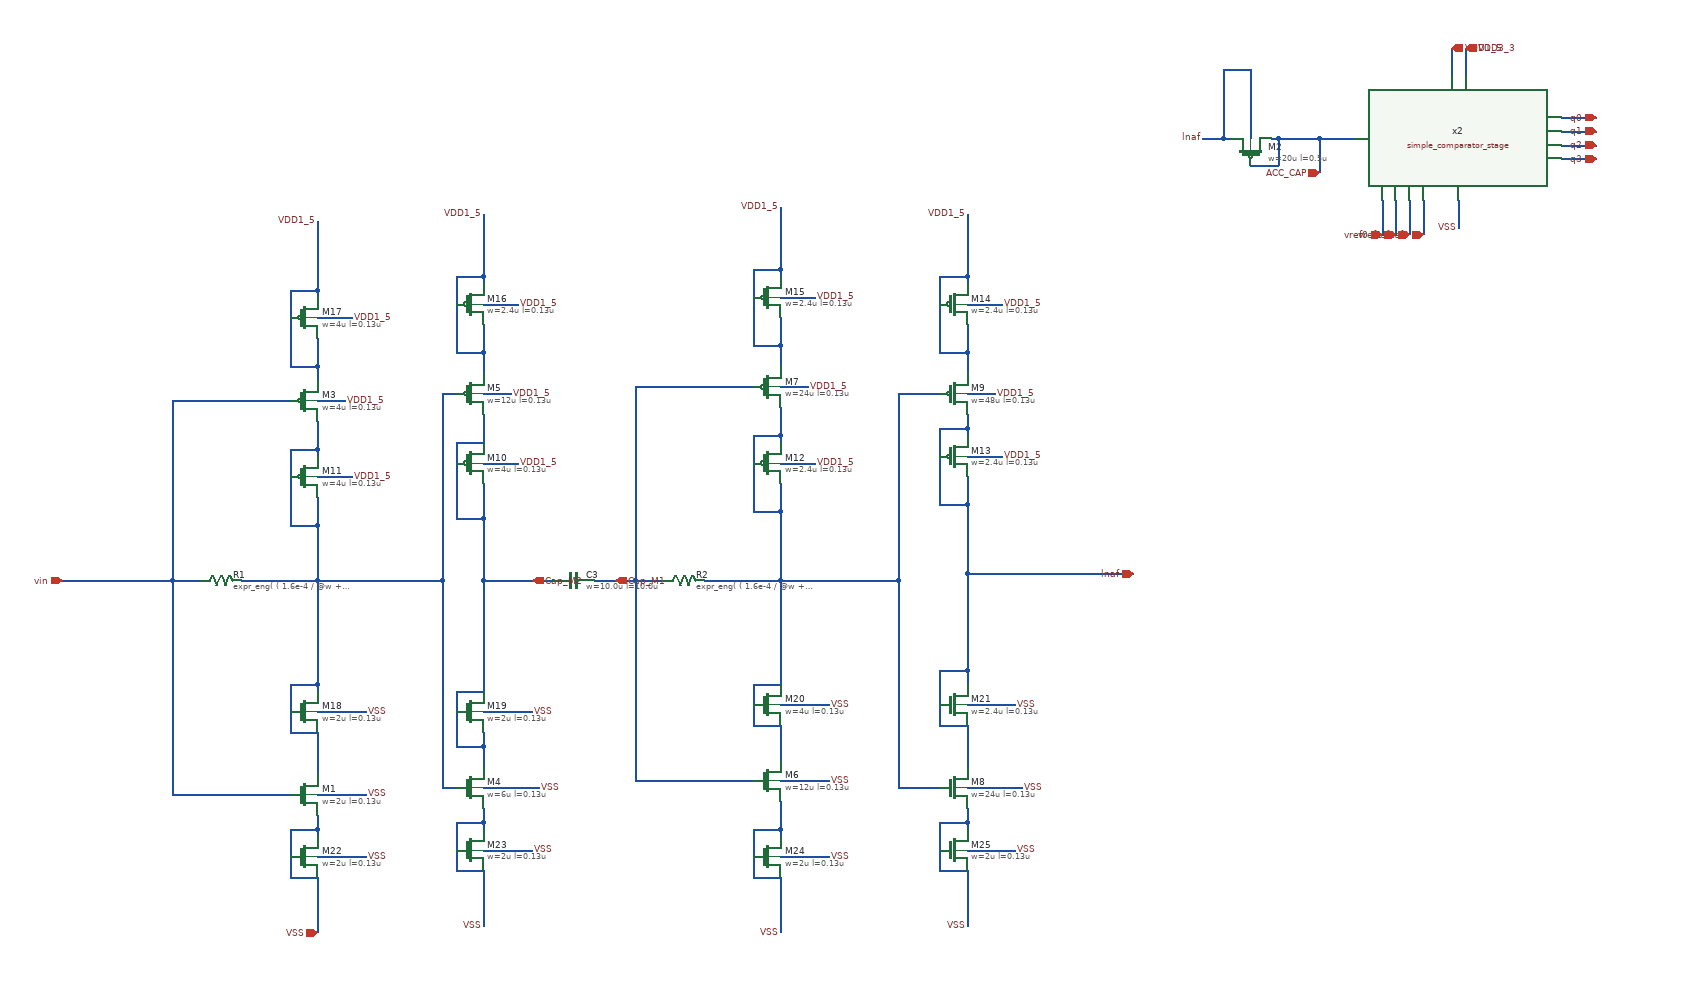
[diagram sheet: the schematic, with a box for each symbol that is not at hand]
v {xschem version=3.4.8RC file_version=1.3}
G {}
K {}
V {}
S {}
F {}
E {}
N 2230 -1650 2230 -1610 {lab=VDD3_3}
N 2210 -1650 2210 -1610 {lab=VDD1_5}
N 2370 -1490 2420 -1490 {lab=q3}
N 2370 -1510 2420 -1510 {lab=q2}
N 2370 -1530 2420 -1530 {lab=q1}
N 2370 -1550 2420 -1550 {lab=q0}
N 2020 -1520 2020 -1470 {lab=ACC_CAP}
N 2110 -1430 2110 -1380 {lab=vref0}
N 2130 -1430 2130 -1380 {lab=vref1}
N 2150 -1430 2150 -1380 {lab=vref2}
N 2170 -1430 2170 -1380 {lab=vref3}
N 2220 -1430 2220 -1390 {lab=VSS}
N 1880 -1520 1890 -1520 {lab=lnaf}
N 1920 -1480 1960 -1480 {lab=ACC_CAP}
N 1960 -1520 1960 -1480 {lab=ACC_CAP}
N 1950 -1520 1960 -1520 {lab=ACC_CAP}
N 1880 -1620 1880 -1520 {lab=lnaf}
N 1880 -1620 1920 -1620 {lab=lnaf}
N 1920 -1620 1920 -1520 {lab=lnaf}
N 1960 -1520 2020 -1520 {lab=ACC_CAP}
N 360 -570 530 -570 {lab=vin}
N 360 -1140 530 -1140 {lab=vin}
N 460 -880 570 -880 {lab=#net1}
N 360 -880 400 -880 {lab=vin}
N 570 -570 640 -570 {lab=VSS}
N 570 -540 570 -520 {lab=VSS}
N 200 -880 360 -880 {lab=vin}
N 570 -880 750 -880 {lab=#net1}
N 810 -1150 850 -1150 {lab=VDD1_5}
N 810 -1410 810 -1320 {lab=VDD1_5}
N 810 -550 810 -530 {lab=VSS}
N 750 -1150 770 -1150 {lab=#net1}
N 750 -580 770 -580 {lab=#net1}
N 1030 -590 1200 -590 {lab=Cap_M1}
N 1030 -1160 1200 -1160 {lab=Cap_M1}
N 1130 -880 1240 -880 {lab=#net2}
N 1030 -880 1070 -880 {lab=Cap_M1}
N 1240 -1160 1280 -1160 {lab=VDD1_5}
N 1240 -1420 1240 -1330 {lab=VDD1_5}
N 1240 -560 1240 -520 {lab=VSS}
N 1240 -880 1240 -730 {lab=#net2}
N 970 -880 1030 -880 {lab=Cap_M1}
N 810 -880 910 -880 {lab=Cap_M2}
N 1510 -1150 1550 -1150 {lab=VDD1_5}
N 1510 -1410 1510 -1320 {lab=VDD1_5}
N 1510 -550 1510 -530 {lab=VSS}
N 1410 -580 1470 -580 {lab=#net2}
N 1410 -1150 1470 -1150 {lab=#net2}
N 1240 -880 1410 -880 {lab=#net2}
N 1510 -890 1750 -890 {lab=lnaf}
N 570 -1190 570 -1170 {lab=VDD1_5}
N 570 -1140 610 -1140 {lab=VDD1_5}
N 570 -1400 570 -1300 {lab=VDD1_5}
N 1510 -1100 1510 -1090 {lab=lnaf}
N 1470 -990 1510 -990 {lab=lnaf}
N 1510 -1030 1510 -990 {lab=lnaf}
N 1470 -1100 1470 -990 {lab=lnaf}
N 1470 -1100 1510 -1100 {lab=lnaf}
N 1510 -1120 1510 -1100 {lab=lnaf}
N 1200 -980 1240 -980 {lab=#net2}
N 1240 -1020 1240 -980 {lab=#net2}
N 1200 -1090 1200 -980 {lab=#net2}
N 1200 -1090 1240 -1090 {lab=#net2}
N 1240 -1090 1240 -1080 {lab=#net2}
N 1240 -1130 1240 -1090 {lab=#net2}
N 770 -970 810 -970 {lab=Cap_M2}
N 770 -1080 770 -970 {lab=Cap_M2}
N 770 -1080 810 -1080 {lab=Cap_M2}
N 810 -1120 810 -1080 {lab=Cap_M2}
N 530 -960 570 -960 {lab=#net1}
N 530 -1070 530 -960 {lab=#net1}
N 530 -1070 570 -1070 {lab=#net1}
N 570 -1070 570 -1060 {lab=#net1}
N 570 -1110 570 -1070 {lab=#net1}
N 570 -880 570 -730 {lab=#net1}
N 570 -1000 570 -960 {lab=#net1}
N 810 -880 810 -720 {lab=Cap_M2}
N 360 -880 360 -570 {lab=vin}
N 750 -880 750 -580 {lab=#net1}
N 1240 -980 1240 -880 {lab=#net2}
N 1030 -880 1030 -590 {lab=Cap_M1}
N 1410 -1150 1410 -880 {lab=#net2}
N 1240 -1050 1290 -1050 {lab=VDD1_5}
N 1510 -1060 1560 -1060 {lab=VDD1_5}
N 810 -1050 860 -1050 {lab=VDD1_5}
N 570 -1030 620 -1030 {lab=VDD1_5}
N 1510 -990 1510 -890 {lab=lnaf}
N 1510 -1320 1510 -1310 {lab=VDD1_5}
N 1470 -1210 1510 -1210 {lab=VDD1_5}
N 1510 -1250 1510 -1210 {lab=VDD1_5}
N 1470 -1320 1470 -1210 {lab=VDD1_5}
N 1470 -1320 1510 -1320 {lab=VDD1_5}
N 1510 -1280 1560 -1280 {lab=VDD1_5}
N 1510 -1210 1510 -1180 {lab=VDD1_5}
N 1200 -1220 1240 -1220 {lab=VDD1_5}
N 1240 -1260 1240 -1220 {lab=VDD1_5}
N 1200 -1330 1200 -1220 {lab=VDD1_5}
N 1200 -1330 1240 -1330 {lab=VDD1_5}
N 1240 -1330 1240 -1320 {lab=VDD1_5}
N 1240 -1290 1290 -1290 {lab=VDD1_5}
N 1240 -1220 1240 -1190 {lab=VDD1_5}
N 770 -1210 810 -1210 {lab=VDD1_5}
N 810 -1250 810 -1210 {lab=VDD1_5}
N 770 -1320 770 -1210 {lab=VDD1_5}
N 770 -1320 810 -1320 {lab=VDD1_5}
N 810 -1320 810 -1310 {lab=VDD1_5}
N 810 -1280 860 -1280 {lab=VDD1_5}
N 810 -1210 810 -1180 {lab=VDD1_5}
N 530 -1190 570 -1190 {lab=VDD1_5}
N 530 -1300 530 -1190 {lab=VDD1_5}
N 530 -1300 570 -1300 {lab=VDD1_5}
N 570 -1300 570 -1290 {lab=VDD1_5}
N 570 -1230 570 -1190 {lab=VDD1_5}
N 570 -1260 620 -1260 {lab=VDD1_5}
N 2020 -1520 2070 -1520 {lab=ACC_CAP}
N 1850 -1520 1880 -1520 {lab=lnaf}
N 1410 -880 1410 -580 {lab=#net2}
N 1470 -750 1470 -670 {lab=lnaf}
N 1470 -750 1510 -750 {lab=lnaf}
N 1510 -890 1510 -750 {lab=lnaf}
N 1510 -750 1510 -730 {lab=lnaf}
N 1510 -670 1510 -610 {lab=lnaf}
N 1470 -670 1510 -670 {lab=lnaf}
N 1510 -700 1580 -700 {lab=VSS}
N 1240 -590 1310 -590 {lab=VSS}
N 1240 -700 1310 -700 {lab=VSS}
N 1240 -670 1240 -620 {lab=#net2}
N 1200 -670 1240 -670 {lab=#net2}
N 1200 -730 1200 -670 {lab=#net2}
N 1200 -730 1240 -730 {lab=#net2}
N 810 -640 810 -610 {lab=Cap_M2}
N 770 -640 810 -640 {lab=Cap_M2}
N 810 -660 810 -640 {lab=Cap_M2}
N 770 -720 770 -640 {lab=Cap_M2}
N 770 -720 810 -720 {lab=Cap_M2}
N 530 -660 570 -660 {lab=#net1}
N 530 -730 530 -660 {lab=#net1}
N 530 -730 570 -730 {lab=#net1}
N 570 -730 570 -720 {lab=#net1}
N 570 -660 570 -600 {lab=#net1}
N 810 -690 880 -690 {lab=VSS}
N 570 -690 640 -690 {lab=VSS}
N 530 -450 570 -450 {lab=VSS}
N 530 -520 530 -450 {lab=VSS}
N 530 -520 570 -520 {lab=VSS}
N 570 -520 570 -510 {lab=VSS}
N 570 -480 640 -480 {lab=VSS}
N 770 -460 810 -460 {lab=VSS}
N 770 -530 770 -460 {lab=VSS}
N 770 -530 810 -530 {lab=VSS}
N 810 -530 810 -520 {lab=VSS}
N 810 -490 880 -490 {lab=VSS}
N 1200 -450 1240 -450 {lab=VSS}
N 1200 -520 1200 -450 {lab=VSS}
N 1200 -520 1240 -520 {lab=VSS}
N 1240 -520 1240 -510 {lab=VSS}
N 1240 -480 1310 -480 {lab=VSS}
N 1470 -460 1510 -460 {lab=VSS}
N 1470 -530 1470 -460 {lab=VSS}
N 1470 -530 1510 -530 {lab=VSS}
N 1510 -530 1510 -520 {lab=VSS}
N 1510 -490 1580 -490 {lab=VSS}
N 1510 -580 1590 -580 {lab=VSS}
N 810 -580 890 -580 {lab=VSS}
N 570 -450 570 -370 {lab=VSS}
N 810 -460 810 -380 {lab=VSS}
N 1240 -450 1240 -370 {lab=VSS}
N 1510 -460 1510 -380 {lab=VSS}
N 810 -1020 810 -970 {lab=Cap_M2}
N 1030 -1160 1030 -880 {lab=Cap_M1}
N 810 -970 810 -880 {lab=Cap_M2}
N 570 -960 570 -880 {lab=#net1}
N 750 -1150 750 -880 {lab=#net1}
N 360 -1140 360 -880 {lab=vin}
C {title-3.sym} 0 0 0 0 {name=l1 author="Belal ELshinnawey" rev=1.0 lock=true}
C {devices/iopin.sym} 570 -370 1 0 {name=p3 lab=VSS}
C {devices/ipin.sym} 200 -880 0 0 {name=p4 lab=vin}
C {devices/iopin.sym} 2420 -1490 0 0 {name=p5 lab=q3}
C {devices/iopin.sym} 2210 -1650 1 1 {name=p1 lab=VDD1_5}
C {devices/lab_pin.sym} 2220 -1390 3 0 {name=l5 sig_type=std_logic lab=VSS}
C {devices/iopin.sym} 2420 -1510 0 0 {name=p2 lab=q2}
C {devices/iopin.sym} 2420 -1530 0 0 {name=p7 lab=q1}
C {devices/iopin.sym} 2420 -1550 0 0 {name=p8 lab=q0}
C {devices/iopin.sym} 2020 -1470 1 0 {name=p9 lab=ACC_CAP}
C {devices/iopin.sym} 2170 -1380 1 0 {name=p16 lab=vref3}
C {devices/iopin.sym} 2150 -1380 1 0 {name=p17 lab=vref2}
C {devices/iopin.sym} 2130 -1380 1 0 {name=p18 lab=vref1}
C {devices/iopin.sym} 2110 -1380 1 0 {name=p19 lab=vref0}
C {simple_comparator_stage.sym} 2220 -1520 0 0 {name=x2}
C {sg13cmos5l_pr/sg13_hv_pmos.sym} 1920 -1500 3 0 {name=M2
l=0.5u
w=20u
 ng=10
 m=1
  mm_ok=1
 model=sg13_hv_pmos
spiceprefix=X
}
C {devices/iopin.sym} 1750 -890 3 0 {name=p14 lab=lnaf}
C {sg13cmos5l_pr/sg13_lv_nmos.sym} 550 -570 0 0 {name=M1
l=0.13u
w=2u
ng=1
m=1
mm_ok=1
model=sg13_lv_nmos
spiceprefix=X
}
C {sg13cmos5l_pr/rhigh.sym} 430 -880 3 0 {name=R1
w=2e-6
l=3.85e-6
model=rhigh
body=VSS
spiceprefix=X
b=0
 m=1
  mm_ok=1
value="expr_eng(  ( 1.6e-4 / @w + 1360.0 * ( (@b + 1)* @l + ( 1.081*( @w - 0.04e-6 ) + 0.18e-6 )*@b ) / ( @w - 0.04e-6 ) ) / @m  )"
}
C {sg13cmos5l_pr/sg13_lv_nmos.sym} 790 -580 0 0 {name=M4
l=0.13u
w=6u
ng=3
m=1
mm_ok=1
model=sg13_lv_nmos
spiceprefix=X
}
C {sg13cmos5l_pr/sg13_lv_pmos.sym} 790 -1150 0 0 {name=M5
l=0.13u
w=12u
ng=3
m=1
mm_ok=1
model=sg13_lv_pmos
spiceprefix=X
}
C {sg13cmos5l_pr/sg13_lv_nmos.sym} 1220 -590 0 0 {name=M6
l=0.13u
w=12u
ng=3
m=1
mm_ok=1
model=sg13_lv_nmos
spiceprefix=X
}
C {sg13cmos5l_pr/sg13_lv_pmos.sym} 1220 -1160 0 0 {name=M7
l=0.13u
w=24u
ng=10
m=1
mm_ok=1
model=sg13_lv_pmos
spiceprefix=X
}
C {sg13cmos5l_pr/rhigh.sym} 1100 -880 3 0 {name=R2
w=2e-6
l=3.85e-6
model=rhigh
body=VSS
spiceprefix=X
b=0
 m=1
  mm_ok=1
value="expr_eng(  ( 1.6e-4 / @w + 1360.0 * ( (@b + 1)* @l + ( 1.081*( @w - 0.04e-6 ) + 0.18e-6 )*@b ) / ( @w - 0.04e-6 ) ) / @m  )"
}
C {sg13cmos5l_pr/cap_mfringe.sym} 940 -880 1 0 {name=C3
model=cap_mfringe
w=10.0u
l=10.0u
mmin=3
mmax=4
spiceprefix=X
spice_ignore=true}
C {sg13cmos5l_pr/sg13_lv_nmos.sym} 1490 -580 0 0 {name=M8
l=0.13u
w=24u
ng=10
m=1
mm_ok=1
model=sg13_lv_nmos
spiceprefix=X
}
C {sg13cmos5l_pr/sg13_lv_pmos.sym} 1490 -1150 0 0 {name=M9
l=0.13u
w=48u
ng=20
m=1
mm_ok=1
model=sg13_lv_pmos
spiceprefix=X
}
C {devices/iopin.sym} 880 -880 3 1 {name=p15 lab=Cap_M2}
C {devices/iopin.sym} 1000 -880 3 1 {name=p21 lab=Cap_M1}
C {devices/iopin.sym} 2230 -1650 1 1 {name=p6 lab=VDD3_3}
C {devices/lab_pin.sym} 810 -380 3 0 {name=l2 sig_type=std_logic lab=VSS}
C {devices/lab_pin.sym} 810 -1410 1 0 {name=l7 sig_type=std_logic lab=VDD1_5
}
C {devices/lab_pin.sym} 1240 -1420 1 0 {name=l8 sig_type=std_logic lab=VDD1_5
}
C {devices/lab_pin.sym} 1510 -1410 1 0 {name=l9 sig_type=std_logic lab=VDD1_5
}
C {sg13cmos5l_pr/sg13_lv_pmos.sym} 550 -1140 0 0 {name=M3
l=0.13u
w=4u
ng=1
m=1
mm_ok=1
model=sg13_lv_pmos
spiceprefix=X
}
C {devices/lab_pin.sym} 570 -1400 1 0 {name=l6 sig_type=std_logic lab=VDD1_5
}
C {sg13cmos5l_pr/sg13_lv_pmos.sym} 790 -1050 0 0 {name=M10
l=0.13u
w=4u
ng=1
m=1
mm_ok=1
model=sg13_lv_pmos
spiceprefix=X
}
C {sg13cmos5l_pr/sg13_lv_pmos.sym} 550 -1030 0 0 {name=M11
l=0.13u
w=4u
ng=1
m=1
mm_ok=1
model=sg13_lv_pmos
spiceprefix=X
}
C {sg13cmos5l_pr/sg13_lv_pmos.sym} 1220 -1050 0 0 {name=M12
l=0.13u
w=2.4u
ng=1
m=1
mm_ok=1
model=sg13_lv_pmos
spiceprefix=X
}
C {sg13cmos5l_pr/sg13_lv_pmos.sym} 1490 -1060 0 0 {name=M13
l=0.13u
w=2.4u
ng=1
m=1
mm_ok=1
model=sg13_lv_pmos
spiceprefix=X
}
C {devices/lab_pin.sym} 1290 -1050 0 1 {name=l10 sig_type=std_logic lab=VDD1_5
}
C {devices/lab_pin.sym} 1560 -1060 0 1 {name=l11 sig_type=std_logic lab=VDD1_5
}
C {devices/lab_pin.sym} 860 -1050 0 1 {name=l12 sig_type=std_logic lab=VDD1_5
}
C {devices/lab_pin.sym} 620 -1030 0 1 {name=l13 sig_type=std_logic lab=VDD1_5
}
C {sg13cmos5l_pr/sg13_lv_pmos.sym} 1490 -1280 0 0 {name=M14
l=0.13u
w=2.4u
ng=1
m=1
mm_ok=1
model=sg13_lv_pmos
spiceprefix=X
}
C {devices/lab_pin.sym} 1560 -1280 0 1 {name=l14 sig_type=std_logic lab=VDD1_5
}
C {sg13cmos5l_pr/sg13_lv_pmos.sym} 1220 -1290 0 0 {name=M15
l=0.13u
w=2.4u
ng=1
m=1
mm_ok=1
model=sg13_lv_pmos
spiceprefix=X
}
C {devices/lab_pin.sym} 1290 -1290 0 1 {name=l15 sig_type=std_logic lab=VDD1_5
}
C {sg13cmos5l_pr/sg13_lv_pmos.sym} 790 -1280 0 0 {name=M16
l=0.13u
w=2.4u
ng=1
m=1
mm_ok=1
model=sg13_lv_pmos
spiceprefix=X
}
C {devices/lab_pin.sym} 860 -1280 0 1 {name=l16 sig_type=std_logic lab=VDD1_5
}
C {devices/lab_pin.sym} 850 -1150 0 1 {name=l17 sig_type=std_logic lab=VDD1_5
}
C {devices/lab_pin.sym} 1280 -1160 0 1 {name=l18 sig_type=std_logic lab=VDD1_5
}
C {devices/lab_pin.sym} 1550 -1150 0 1 {name=l19 sig_type=std_logic lab=VDD1_5
}
C {sg13cmos5l_pr/sg13_lv_pmos.sym} 550 -1260 0 0 {name=M17
l=0.13u
w=4u
ng=1
m=1
mm_ok=1
model=sg13_lv_pmos
spiceprefix=X
}
C {devices/lab_pin.sym} 620 -1260 0 1 {name=l20 sig_type=std_logic lab=VDD1_5
}
C {devices/lab_pin.sym} 610 -1140 0 1 {name=l21 sig_type=std_logic lab=VDD1_5
}
C {devices/lab_pin.sym} 1850 -1520 3 0 {name=l22 sig_type=std_logic lab=lnaf}
C {sg13cmos5l_pr/sg13_lv_nmos.sym} 550 -690 0 0 {name=M18
l=0.13u
w=2u
ng=1
m=1
mm_ok=1
model=sg13_lv_nmos
spiceprefix=X
}
C {sg13cmos5l_pr/sg13_lv_nmos.sym} 790 -690 0 0 {name=M19
l=0.13u
w=2u
ng=1
m=1
mm_ok=1
model=sg13_lv_nmos
spiceprefix=X
}
C {sg13cmos5l_pr/sg13_lv_nmos.sym} 1220 -700 0 0 {name=M20
l=0.13u
w=4u
ng=1
m=1
mm_ok=1
model=sg13_lv_nmos
spiceprefix=X
}
C {sg13cmos5l_pr/sg13_lv_nmos.sym} 1490 -700 0 0 {name=M21
l=0.13u
w=2.4u
ng=1
m=1
mm_ok=1
model=sg13_lv_nmos
spiceprefix=X
}
C {devices/lab_pin.sym} 1580 -700 2 0 {name=l23 sig_type=std_logic lab=VSS}
C {devices/lab_pin.sym} 1310 -700 2 0 {name=l24 sig_type=std_logic lab=VSS}
C {devices/lab_pin.sym} 880 -690 2 0 {name=l25 sig_type=std_logic lab=VSS}
C {devices/lab_pin.sym} 640 -690 2 0 {name=l26 sig_type=std_logic lab=VSS}
C {sg13cmos5l_pr/sg13_lv_nmos.sym} 550 -480 0 0 {name=M22
l=0.13u
w=2u
ng=1
m=1
mm_ok=1
model=sg13_lv_nmos
spiceprefix=X
}
C {devices/lab_pin.sym} 640 -480 2 0 {name=l27 sig_type=std_logic lab=VSS}
C {sg13cmos5l_pr/sg13_lv_nmos.sym} 790 -490 0 0 {name=M23
l=0.13u
w=2u
ng=1
m=1
mm_ok=1
model=sg13_lv_nmos
spiceprefix=X
}
C {devices/lab_pin.sym} 880 -490 2 0 {name=l28 sig_type=std_logic lab=VSS}
C {sg13cmos5l_pr/sg13_lv_nmos.sym} 1220 -480 0 0 {name=M24
l=0.13u
w=2u
ng=1
m=1
mm_ok=1
model=sg13_lv_nmos
spiceprefix=X
}
C {devices/lab_pin.sym} 1310 -480 2 0 {name=l29 sig_type=std_logic lab=VSS}
C {sg13cmos5l_pr/sg13_lv_nmos.sym} 1490 -490 0 0 {name=M25
l=0.13u
w=2u
ng=1
m=1
mm_ok=1
model=sg13_lv_nmos
spiceprefix=X
}
C {devices/lab_pin.sym} 1580 -490 2 0 {name=l30 sig_type=std_logic lab=VSS}
C {devices/lab_pin.sym} 1590 -580 2 0 {name=l31 sig_type=std_logic lab=VSS}
C {devices/lab_pin.sym} 1310 -590 2 0 {name=l32 sig_type=std_logic lab=VSS}
C {devices/lab_pin.sym} 890 -580 2 0 {name=l33 sig_type=std_logic lab=VSS}
C {devices/lab_pin.sym} 640 -570 2 0 {name=l34 sig_type=std_logic lab=VSS}
C {devices/lab_pin.sym} 1240 -370 3 0 {name=l3 sig_type=std_logic lab=VSS}
C {devices/lab_pin.sym} 1510 -380 3 0 {name=l4 sig_type=std_logic lab=VSS}
